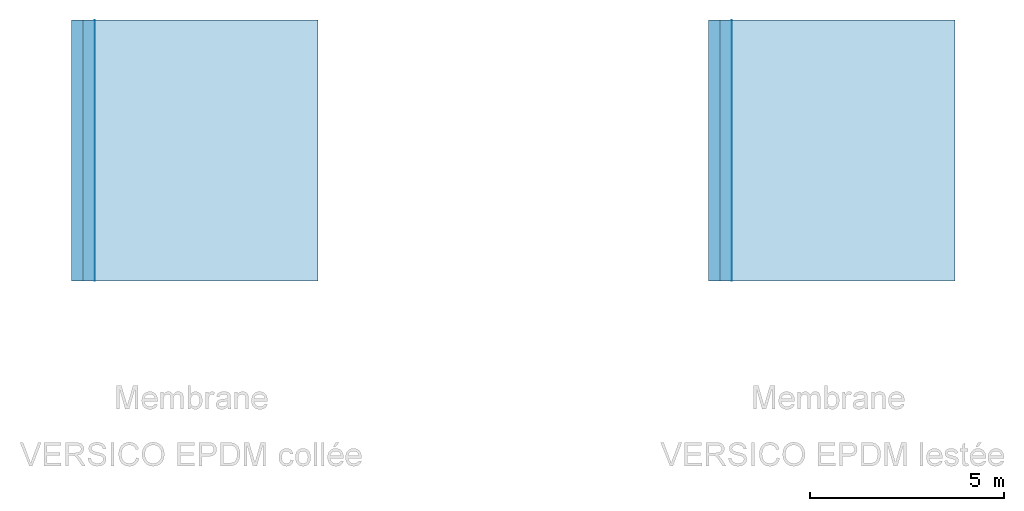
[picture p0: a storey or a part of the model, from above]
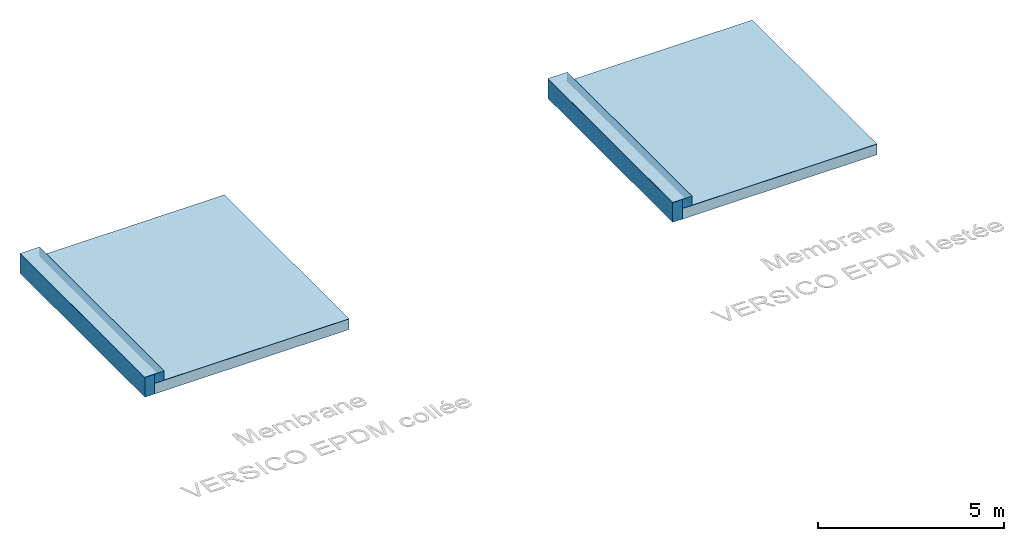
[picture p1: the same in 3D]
Properties of the parts of a building model (IFC2X3)

# File
Description: ViewDefinition [CoordinationView_V2.0, QuantityTakeOffAddOnView], RevitIdentifiers [ContentGUID: ba8bcfdc-dbaa-49fa-ac56-a6aa088a99af, VersionGUID: 456010b6-1bde-40f1-8411-57aa6fc5e552, NumberOfSaves: 115], CoordinateReference [CoordinateBase: Coordonnées partagées, ProjectSite: Interne]
File name: FR_Toit_VMBSO_VERSICO_MEMBRANE_EPDM.ifc
Time: 2026-10-01T16:57:31+01:00
Written by: ODA SDAI 25.12
Made in: Autodesk - Revit 26.4.0.32 (FRA) - 26.4.0.32

# IfcSite, Default
RefLatitude: 42, 24, 53, 508911; RefLongitude: -71, -15, -29, -58837; RefElevation: 0 mm
Autre - Catégorie: Informations sur le projet

# IfcBuilding
Pset_BuildingCommon - NumberOfStoreys: 1
Autre - Catégorie: Informations sur le projet

# IfcBuildingStorey, Niveau 1
LongName: Niveau 1; Elevation: 0 mm
Autre - Catégorie: Niveaux; Famille: Niveau; Famille et type: Niveau: Niveau 1; ID du type: 1520; Type: Niveau 1
Contraintes - Elévation: 0 mm
Cotes - Hauteur de calcul: 0 mm
Données d'identification - Structure: no; Etage de bâtiment: yes; Nom: Niveau 1
Autre(Type) - Catégorie: Niveaux; Nom de la famille: Niveau
Contraintes(Type) - Référence de l'élévation: Point de base du projet
Graphismes(Type) - Couleur: 0; Epaisseur des lignes: 1; Motif des lignes: Plein; Valeur par défaut du symbole à l'extrémité 1: no; Valeur par défaut du symbole à l'extrémité 2: yes
Données d'identification(Type) - Nom du type: Niveau 1

# IfcBuildingElementProxy: Texte 3D:Model Text 1 (2)
In: Niveau 1
Type - Autre - Catégorie: Modèles génériques; Nom de la famille: Texte 3D
Type - Données d'identification - Nom du type: Model Text 1
Type - Texte - Gras: no; Italique: no; Police de texte: Arial; Taille du texte: 600 mm
Pset_BuildingElementProxyCommon - Reference: Model Text 1; sets with these values: 2
Autre - Famille: Texte 3D; Famille et type: Texte 3D: Model Text 1; ID du type: 2370; Type: Model Text 1
Contraintes - Plan de construction: <non associé>
Cotes - Profondeur: 10 mm
Graphismes - Alignement horizontal: Centre
Données d'identification - Sous-catégorie: Modèles génériques
Phase de construction - Phase de création: Nouvelle construction
Name (Texte 3D:Model Text 1:...) | Texte
24701 | Membrane VERSICO EPDM collée
24706 | Membrane VERSICO EPDM lestée

# IfcRoof (6)
In: Niveau 1
Pset_RoofCommon - IsExternal: yes
Autre - Catégorie: Toits; Famille: Toit de base
Contraintes - Décalage de la coupure: 0 mm; Lié au volume: no; Limite de pièce: yes; Niveau de base: Niveau 1
Construction - Coupe en chevron: Coupe verticale; Profondeur du bord de toiture: 0 mm
Phase de construction - Phase de création: Nouvelle construction
Name (Toit de base:...) | Material | Pset_QuantityTakeOff, Reference = Pset_RoofCommon, Reference = Type | ProjectedArea (m2) = TotalArea (m2) = GrossArea (m2) = NetArea (m2) = Surface (m2) | Famille et type | ID du type | Décalage inférieur à partir du niveau (mm) | Hauteur maximale de l'arrête (mm) | Epaisseur (mm) | Volume (m3)
Membrane VERSICO EPDM Partie courante collée:25614 | Membrane VERSICO EPDM collée_Partie courante 1.2 mm, Adhésif de contact 1.1 mm | Membrane VERSICO EPDM Partie courante collée | 38.5877 | Toit de base: Membrane VERSICO EPDM Partie courante collée | 13271 | 135.2 | 137.5 | 2.3 | 0.0887517 | Cotes - Inclinaison: 0
Membrane VERSICO EPDM Partie courante lestée:26349 | Film de protection polyester 0.8 mm, Membrane VERSICO EPDM lestée_Partie courante 1.5 mm | Membrane VERSICO EPDM Partie courante lestée | 38.5877 | Toit de base: Membrane VERSICO EPDM Partie courante lestée | 23930 | 135.2 | 137.5 | 2.3 | 0.0887517 | Cotes - Inclinaison: 0
Membrane VERSICO EPDM_Acrotère:31611 | Membrane VERSICO EPDM collée_Acrotère/Relevé 1.5 mm, Adhésif de contact 1.1 mm | Membrane VERSICO EPDM_Acrotère | 4.05083 | Toit de base: Membrane VERSICO EPDM_Acrotère | 19271 | 435.2 | 437.8 | 2.6 | 0.0105322 | Pset_ManufacturerTypeInformation - Manufacturer: VM BUILDING SOLUTIONS
Toit-Support autorisé:31936 | Isolation 100 mm, <Unnamed> 0.8 mm, Béton de pente 50 mm, Structure porteuse 200 mm | Toit-Support autorisé | 40.602 | Toit de base: Toit-Support autorisé | 31943 | -215.6 | 135.2 | 350.8 | 14.2432
Toit-Support autorisé:32010 | Isolation 100 mm, <Unnamed> 0.8 mm, Béton de pente 50 mm, Structure porteuse 200 mm | Toit-Support autorisé | 40.602 | Toit de base: Toit-Support autorisé | 31943 | -215.6 | 135.2 | 350.8 | 14.2432
Membrane VERSICO EPDM_Acrotère:32271 | Membrane VERSICO EPDM collée_Acrotère/Relevé 1.5 mm, Adhésif de contact 1.1 mm | Membrane VERSICO EPDM_Acrotère | 4.05083 | Toit de base: Membrane VERSICO EPDM_Acrotère | 19271 | 435.2 | 437.8 | 2.6 | 0.0105322 | Pset_ManufacturerTypeInformation - Manufacturer: VM BUILDING SOLUTIONS

# IfcSlab: Toit de base:Membrane VERSICO EPDM Partie courante collée, Toit de base:Membrane VERSICO EPDM Partie courante collée:25614
In: Niveau 1
Type - PredefinedType: ROOF
Type - Autre - Catégorie: Toits; Nom de la famille: Toit de base
Type - Construction - Climat: Zones de vent 1 à 4 (hors zone 5 et DROM) et climat de plaine.; Conditions particulières: De faible à moyenne sur support bois. De faible à forte sur maçonnerie. Faible à très forte hygrométrie sur tôle d'acier nervurée.; Document de référence: DTA n°5.2/19-2644_V2, CCT Carlisle Septembre 2016; Epaisseur: 1,2 mm - 1,5 mm; Epaisseur par défaut: 2.3 mm; Masse surfacique: 1,4 kg/m² (pour 1,2 mm) et 1,90 kg/m² (pour 1,5 mm); Mise en œuvre: Adhérence totale ou partielle. Installation libre sous le lestage; N° DTU: DTU de la série 43; Résistance au feu: Classe E Norme d'essai; Supports autorisés: Maçonnerie, Béton cellulaire, Bois et dérivés du bois, Isolation (laine minérale soudable, perlite expansée soudable, verre cellulaire, PIR, PUR, polystyrène…), Anciennes membranes bitumineuses; Type de toit: Nouvelle construction et rénovation, toiture accessible, technique ou non accessible de pente conforme à la norme NF P 84 série 200 (DTU série 43)
Type - Graphismes - Couleur vue détail faible: 0
Type - Données d'identification - Code Produit: E788; Commentaires du type: Membrane VERSICO EPDM collée; Description: Versico est une membrane EPDM non renforcée. Disponible avec pretape. Gamme standard.; Fournisseur: VM Building Solutions; Identifiant du type: VERSICO; Modèle: Membrane VERSICO EPDM collée; Nom du type: Membrane VERSICO EPDM Partie courante collée; URL: https://www.vmbuildingsolutions.com/fr-fr/epdm/membrane-epdm-versico
Type - Matériaux et finitions - Matériau principal: Membrane EPDM caoutchouc VERSICO
Type - Propriétés analytiques - Coefficient d'absorbance: 0.1; Rugosité: 1
Type - Pset_ReinforcementBarPitchOfSlab - Description: Versico est une membrane EPDM non renforcée. Disponible avec pretape. Gamme standard.
Material: Membrane VERSICO EPDM collée_Partie courante 1.2 mm, Adhésif de contact 1.1 mm
Pset_QuantityTakeOff - Reference: Membrane VERSICO EPDM Partie courante collée; sets with these values: 2
Pset_SlabCommon - Reference: Membrane VERSICO EPDM Partie courante collée; IsExternal: yes; PitchAngle: 0 deg
BaseQuantities - NetArea: 3.58491 m2; NetVolume: 0.0082453 m3; GrossArea: 38.5877 m2; GrossVolume: 0.0082453 m3; Perimeter: 24922.8 mm

# IfcSlab: Toit de base:Membrane VERSICO EPDM Partie courante lestée, Toit de base:Membrane VERSICO EPDM Partie courante lestée:26349
In: Niveau 1
Type - PredefinedType: ROOF
Type - Autre - Catégorie: Toits; Nom de la famille: Toit de base
Type - Construction - Conditions particulières: De faible à moyenne sur support bois. De faible à forte sur maçonnerie. Faible à très forte hygrométrie sur tôle d'acier nervurée.; Document de référence: DTA n°5.2/19-2644_V2, CCT Carlisle Septembre 2016 ATG 07/2247 Rèles Professionnelles pour la conception et la réalisation des terrasses et toitures végétalisées édition n°2 – novembre 2007. ATG 07/2247 Rèles Professionnelles pour la conception et la réalisation des terrasses et toitures végétalisées édition n°2 – novembre 2007.; Epaisseur: 1,2 mm - 1,5 mm; Epaisseur par défaut: 2.3 mm; Masse surfacique: 1,4 kg/m² (pour 1,2 mm) et 1,90 kg/m² (pour 1,5 mm); Mise en œuvre: Adhérence totale ou partielle. Installation libre sous le lestage; N° DTU: DTU de la série 43; Résistance au feu: Classe E Norme d'essai; Supports autorisés: Maçonnerie, béton cellulaire, bois et dérivés du bois, isolation (PIR surfacé avec support, PUR avec support, laine minérale avec support), anciennes membranes bitumineuses.; Type de toit: Nouvelle construction et rénovation, toiture accessible, technique ou non accessible de pente conforme à la norme NF P 84 série 200 (DTU série 43), ou avis technique du support. En construction neuve ou en rénovation
Type - Graphismes - Couleur vue détail faible: 0
Type - Données d'identification - Code Produit: E788; Commentaires du type: Membrane EPDM VERSICO lestée; Description: Versico est une membrane EPDM non renforcée. Disponible avec pretape. Gamme standard.; Fournisseur: VM Building Solutions; Identifiant du type: VERSICO; Modèle: Membrane EPDM VERSICO lestée; Nom du type: Membrane VERSICO EPDM Partie courante lestée; URL: https://www.vmbuildingsolutions.com/fr-fr/epdm/membrane-epdm-versico
Type - Matériaux et finitions - Matériau principal: Membrane EPDM caoutchouc VERSICO
Type - Propriétés analytiques - Coefficient d'absorbance: 0.1; Rugosité: 1
Type - Pset_ReinforcementBarPitchOfSlab - Description: Versico est une membrane EPDM non renforcée. Disponible avec pretape. Gamme standard.
Material: Film de protection polyester 0.8 mm, Membrane VERSICO EPDM lestée_Partie courante 1.5 mm
Pset_QuantityTakeOff - Reference: Membrane VERSICO EPDM Partie courante lestée; sets with these values: 2
Pset_SlabCommon - IsExternal: yes; PitchAngle: 0 deg; Reference: Membrane VERSICO EPDM Partie courante lestée
BaseQuantities - NetArea: 3.58491 m2; NetVolume: 0.0082453 m3; GrossArea: 38.5877 m2; GrossVolume: 0.0082453 m3; Perimeter: 24922.8 mm

# IfcSlab: Toit de base:Membrane VERSICO EPDM_Acrotère (2)
In: Niveau 1
Type - PredefinedType: ROOF
Type - Autre - Catégorie: Toits; Nom de la famille: Toit de base
Type - Construction - Climat: Zones de vent 1 à 4 (hors zone 5 et DROM) et climat de plaine.; Conditions particulières: De faible à moyenne sur support bois. De faible à forte sur maçonnerie. Faible à très forte hygrométrie sur tôle d'acier nervurée.; Document de référence: DTA n°5.2/19-2644_V2, CCT Carlisle Septembre 2016 ATG 07/2247 Rèles Professionnelles pour la conception et la réalisation des terrasses et toitures végétalisées édition n°2 – novembre 2007.; Epaisseur: 1,2 mm - 1,5 mm; Epaisseur par défaut: 2.6 mm; Masse surfacique: 1,4 kg/m² (pour 1,2 mm) et 1,90 kg/m² (pour 1,5 mm); Mise en œuvre: Adhérence totale; N° DTU: DTU de la série 43; Résistance au feu: Classe E Norme d'essai; Supports autorisés: Maçonnerie, Béton cellulaire, Bois et dérivés du bois, Isolation (laine minérale soudable, perlite expansée soudable, verre cellulaire, PIR, PUR, polystyrène…), Anciennes membranes bitumineuses; Type de toit: Nouvelle construction et rénovation, toiture accessible, technique ou non accessible de pente conforme à la norme NF P 84 série 200 (DTU série 43), ou avis technique du support.
Type - Graphismes - Couleur vue détail faible: 0
Type - Données d'identification - Description: Versico est une membrane EPDM non renforcée. Disponible avec pretape. Gamme standard.; Fabricant: VM BUILDING SOLUTIONS; Fournisseur: VM Building Solutions; Identifiant du type: VERSICO; Modèle: Membrane VERSICO EPDM collée; Nom du type: Membrane VERSICO EPDM_Acrotère; Note d'identification: Membrane VERSICO EPDM collée; URL: https://www.vmbuildingsolutions.com/fr-fr/epdm/membrane-epdm-versico
Type - Matériaux et finitions - Matériau principal: Membrane EPDM caoutchouc VERSICO
Type - Propriétés analytiques - Coefficient d'absorbance: 0.1; Rugosité: 1
Type - Pset_ManufacturerTypeInformation - Manufacturer: VM BUILDING SOLUTIONS
Type - Pset_ReinforcementBarPitchOfSlab - Description: Versico est une membrane EPDM non renforcée. Disponible avec pretape. Gamme standard.
Material: Membrane VERSICO EPDM collée_Acrotère/Relevé 1.5 mm, Adhésif de contact 1.1 mm
Pset_QuantityTakeOff - Reference: Membrane VERSICO EPDM_Acrotère; sets with these values: 2
Pset_SlabCommon - IsExternal: yes; PitchAngle: 0 deg; Reference: Membrane VERSICO EPDM_Acrotère
BaseQuantities - NetArea: 0.376335 m2; NetVolume: 0.000978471 m3; GrossArea: 4.05083 m2; GrossVolume: 0.000978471 m3; Perimeter: 14635.5 mm
Name (Toit de base:Membrane VERSICO EPDM_Acrotère:...)
31611
32271

# IfcSlab: Toit de base:Toit-Support autorisé (2)
In: Niveau 1
Type - PredefinedType: ROOF
Type - Autre - Catégorie: Toits; Nom de la famille: Toit de base
Type - Construction - Epaisseur par défaut: 350.8 mm
Type - Graphismes - Couleur vue détail faible: 0
Type - Données d'identification - Nom du type: Toit-Support autorisé
Type - Propriétés analytiques - Coefficient d'absorbance: 0.1; Rugosité: 1
Material: Isolation 100 mm, <Unnamed> 0.8 mm, Béton de pente 50 mm, Structure porteuse 200 mm
Pset_QuantityTakeOff - Reference: Toit-Support autorisé; sets with these values: 2
Pset_SlabCommon - IsExternal: yes; PitchAngle: 0 deg; Reference: Toit-Support autorisé
BaseQuantities - NetArea: 3.77205 m2; NetVolume: 1.32324 m3; GrossArea: 40.602 m2; GrossVolume: 1.32324 m3; Perimeter: 25522.8 mm
Name (Toit de base:Toit-Support autorisé:...)
31936
32010

# IfcWallStandardCase: Mur de base:Membrane VERSICO EPDM Relevé collé (2)
In: Niveau 1
Type - PredefinedType: STANDARD; Material: Membrane VERSICO EPDM collée_Acrotère/Relevé 1.5 mm, Adhésif de contact 1.1 mm
Type - Autre - Catégorie: Murs; Nom de la famille: Mur de base
Type - Construction - Fonction: Extérieur; Retournement aux extrémités: Aucun(e); Retournement aux insertions: Ne pas retourner; Climat: Zones de vent 1 à 4 (hors zone 5 et DROM) et climat de plaine.; Conditions particulières: Adhérence totale; Largeur: 2.6 mm; Mise en œuvre: Le relevé est entièrement recouvert de Versico entièrement collé à l'aide de l'adhésif de contact Spray fix ou Bonding.; N° DTU: DTU de la série 43; Résistance au feu: Classe E Norme d'essai; Supports autorisés: Maçonnerie, Béton cellulaire, Bois et dérivés du bois, Isolation (laine minérale soudable, perlite expansée soudable, verre cellulaire, PIR, PUR, polystyrène…), Anciennes membranes bitumineuses; Type de toit: Nouvelle construction et rénovation, toiture accessible, technique ou non accessible de pente conforme à la norme NF P 84 série 200 (DTU série 43), ou avis technique du support.
Type - Graphismes - Couleur vue détail faible: 0
Type - Données d'identification - Commentaires du type: Membrane EPDM VERSICO collée; Description: Versico est une membrane EPDM non renforcée. Disponible avec pretape. Gamme standard.; Fournisseur: VM Building Solutions; Identifiant du type: VERSICO; Modèle: Membrane EPDM VERSICO collée; Nom du type: Membrane VERSICO EPDM Relevé collé; URL: https://www.vmbuildingsolutions.com/fr-fr/epdm/membrane-epdm-versico
Type - Matériaux et finitions - Matériau principal: Membrane EPDM caoutchouc VERSICO
Type - Propriétés analytiques - Coefficient d'absorbance: 0.1; Rugosité: 1
Type - Pset_ReinforcementBarPitchOfWall - Description: Versico est une membrane EPDM non renforcée. Disponible avec pretape. Gamme standard.
BaseQuantities - Length: 6714.46 mm; Width: 2.6 mm; GrossFootprintArea: 0.0174576 m2
Pset_QuantityTakeOff - Reference: Membrane VERSICO EPDM Relevé collé; sets with these values: 2
Pset_WallCommon - IsExternal: yes; ExtendToStructure: no; LoadBearing: no; Reference: Membrane VERSICO EPDM Relevé collé
Autre - Famille: Mur de base; Famille et type: Mur de base: Membrane VERSICO EPDM Relevé collé; ID du type: 2373; Type: Membrane VERSICO EPDM Relevé collé
Contraintes - Lié au volume: no; Limite de pièce: yes; Contrainte inférieure: Niveau 1; Décalage supérieur: 0 mm; Extension inférieure: 0 mm; Extension supérieure: 0 mm; Ligne de justification: Axe du mur; Partie inférieure attachée: no; Partie supérieure attachée: no
Cotes - Longueur: 6714.46 mm
Phase de construction - Phase de création: Nouvelle construction
Structure - Structure: no; Utilisation structurelle: Non porteur
Définition de la coupe transversale - Coupe transversale: Vertical
Name (Mur de base:Membrane VERSICO EPDM Relevé collé:...) | Height (mm) | GrossVolume (m3) = NetVolume (m3) = Volume (m3) | GrossSideArea (m2) = NetSideArea (m2) = Surface (m2) | Décalage inférieur (mm) | Hauteur non contrainte (mm)
25628 | 296.7 | 0.00517967 | 1.99218 | 138.5 | 161.5
26363 | 297 | 0.00518491 | 1.9942 | 178.665 | 121.335

# IfcWallStandardCase: Mur de base:Mur 1 (4)
In: Niveau 1
Type - PredefinedType: STANDARD; Material: Isolation 100 mm, <Unnamed> 200 mm
Type - Autre - Catégorie: Murs; Nom de la famille: Mur de base
Type - Construction - Fonction: Extérieur; Largeur: 300 mm; Retournement aux extrémités: Aucun(e); Retournement aux insertions: Ne pas retourner
Type - Graphismes - Couleur vue détail faible: 0
Type - Données d'identification - Nom du type: Mur 1
Type - Propriétés analytiques - Coefficient d'absorbance: 0.1; Rugosité: 1
BaseQuantities - Length: 6714.46 mm; Width: 300 mm; GrossFootprintArea: 2.01434 m2
Pset_QuantityTakeOff - Reference: Mur 1; sets with these values: 2
Pset_WallCommon - IsExternal: yes; Reference: Mur 1; ExtendToStructure: no; LoadBearing: no
Autre - Famille: Mur de base; Famille et type: Mur de base: Mur 1; ID du type: 1557; Type: Mur 1
Contraintes - Lié au volume: no; Limite de pièce: yes; Contrainte inférieure: Niveau 1; Décalage supérieur: 0 mm; Extension inférieure: 0 mm; Extension supérieure: 0 mm; Ligne de justification: Axe du mur; Partie inférieure attachée: no; Partie supérieure attachée: no
Cotes - Longueur: 6714.46 mm
Phase de construction - Phase de création: Nouvelle construction
Structure - Structure: no; Utilisation structurelle: Non porteur
Définition de la coupe transversale - Coupe transversale: Vertical
Name (Mur de base:Mur 1:...) | Height (mm) = Hauteur non contrainte (mm) | GrossVolume (m3) = NetVolume (m3) = Volume (m3) | GrossSideArea (m2) = NetSideArea (m2) = Surface (m2) | Décalage inférieur (mm)
25626 | 650.8 | 1.31093 | 4.36977 | -215.6
25627 | 300 | 0.604302 | 2.01434 | 0
26361 | 650.8 | 1.31093 | 4.36977 | -215.6
26362 | 300 | 0.604302 | 2.01434 | 0
